VERSION 5.7 ;
  NOWIREEXTENSIONATPIN ON ;
  DIVIDERCHAR "/" ;
  BUSBITCHARS "[]" ;
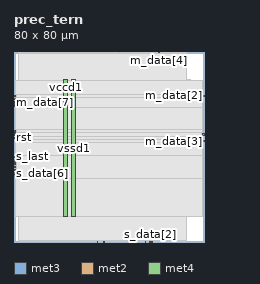
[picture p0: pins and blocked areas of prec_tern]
MACRO prec_tern
  CLASS BLOCK ;
  FOREIGN prec_tern ;
  ORIGIN 0.000 0.000 ;
  SIZE 80.000 BY 80.000 ;
  PIN clk
    DIRECTION INPUT ;
    USE SIGNAL ;
    ANTENNAGATEAREA 1.286700 ;
    ANTENNADIFFAREA 0.434700 ;
    PORT
      LAYER met3 ;
        RECT 0.000 57.160 0.600 57.760 ;
    END
  END clk
  PIN m_data[0]
    DIRECTION OUTPUT ;
    USE SIGNAL ;
    ANTENNADIFFAREA 0.795200 ;
    PORT
      LAYER met2 ;
        RECT 37.810 0.000 38.090 0.280 ;
    END
  END m_data[0]
  PIN m_data[1]
    DIRECTION OUTPUT ;
    USE SIGNAL ;
    ANTENNADIFFAREA 0.795200 ;
    PORT
      LAYER met2 ;
        RECT 35.050 0.000 35.330 0.280 ;
    END
  END m_data[1]
  PIN m_data[2]
    DIRECTION OUTPUT ;
    USE SIGNAL ;
    ANTENNADIFFAREA 0.795200 ;
    PORT
      LAYER met3 ;
        RECT 79.400 61.240 80.000 61.840 ;
    END
  END m_data[2]
  PIN m_data[3]
    DIRECTION OUTPUT ;
    USE SIGNAL ;
    ANTENNADIFFAREA 0.795200 ;
    PORT
      LAYER met3 ;
        RECT 79.400 42.200 80.000 42.800 ;
    END
  END m_data[3]
  PIN m_data[4]
    DIRECTION OUTPUT ;
    USE SIGNAL ;
    ANTENNADIFFAREA 0.795200 ;
    PORT
      LAYER met2 ;
        RECT 60.810 79.720 61.090 80.000 ;
    END
  END m_data[4]
  PIN m_data[5]
    DIRECTION OUTPUT ;
    USE SIGNAL ;
    ANTENNADIFFAREA 0.795200 ;
    PORT
      LAYER met2 ;
        RECT 44.250 79.720 44.530 80.000 ;
    END
  END m_data[5]
  PIN m_data[6]
    DIRECTION OUTPUT ;
    USE SIGNAL ;
    ANTENNADIFFAREA 0.795200 ;
    PORT
      LAYER met3 ;
        RECT 0.000 61.240 0.600 61.840 ;
    END
  END m_data[6]
  PIN m_data[7]
    DIRECTION OUTPUT ;
    USE SIGNAL ;
    ANTENNADIFFAREA 0.795200 ;
    PORT
      LAYER met3 ;
        RECT 0.000 58.520 0.600 59.120 ;
    END
  END m_data[7]
  PIN m_last
    DIRECTION OUTPUT ;
    USE SIGNAL ;
    ANTENNADIFFAREA 0.795200 ;
    PORT
      LAYER met3 ;
        RECT 0.000 59.880 0.600 60.480 ;
    END
  END m_last
  PIN m_ready
    DIRECTION INPUT ;
    USE SIGNAL ;
    ANTENNAGATEAREA 0.647700 ;
    ANTENNADIFFAREA 0.434700 ;
    PORT
      LAYER met3 ;
        RECT 0.000 44.920 0.600 45.520 ;
    END
  END m_ready
  PIN m_valid
    DIRECTION OUTPUT ;
    USE SIGNAL ;
    ANTENNADIFFAREA 0.795200 ;
    PORT
      LAYER met3 ;
        RECT 0.000 46.280 0.600 46.880 ;
    END
  END m_valid
  PIN rst
    DIRECTION INPUT ;
    USE SIGNAL ;
    ANTENNAGATEAREA 0.631200 ;
    ANTENNADIFFAREA 0.434700 ;
    PORT
      LAYER met3 ;
        RECT 0.000 43.560 0.600 44.160 ;
    END
  END rst
  PIN s_data[0]
    DIRECTION INPUT ;
    USE SIGNAL ;
    ANTENNAGATEAREA 0.647700 ;
    ANTENNADIFFAREA 0.434700 ;
    PORT
      LAYER met2 ;
        RECT 55.290 0.000 55.570 0.280 ;
    END
  END s_data[0]
  PIN s_data[1]
    DIRECTION INPUT ;
    USE SIGNAL ;
    ANTENNAGATEAREA 0.647700 ;
    ANTENNADIFFAREA 0.434700 ;
    PORT
      LAYER met2 ;
        RECT 58.050 0.000 58.330 0.280 ;
    END
  END s_data[1]
  PIN s_data[2]
    DIRECTION INPUT ;
    USE SIGNAL ;
    ANTENNAGATEAREA 0.647700 ;
    ANTENNADIFFAREA 0.434700 ;
    PORT
      LAYER met2 ;
        RECT 57.130 0.000 57.410 0.280 ;
    END
  END s_data[2]
  PIN s_data[3]
    DIRECTION INPUT ;
    USE SIGNAL ;
    ANTENNAGATEAREA 0.647700 ;
    ANTENNADIFFAREA 0.434700 ;
    PORT
      LAYER met3 ;
        RECT 79.400 44.920 80.000 45.520 ;
    END
  END s_data[3]
  PIN s_data[4]
    DIRECTION INPUT ;
    USE SIGNAL ;
    ANTENNAGATEAREA 0.647700 ;
    ANTENNADIFFAREA 0.434700 ;
    PORT
      LAYER met3 ;
        RECT 0.000 31.320 0.600 31.920 ;
    END
  END s_data[4]
  PIN s_data[5]
    DIRECTION INPUT ;
    USE SIGNAL ;
    ANTENNAGATEAREA 0.647700 ;
    ANTENNADIFFAREA 0.434700 ;
    PORT
      LAYER met3 ;
        RECT 0.000 27.240 0.600 27.840 ;
    END
  END s_data[5]
  PIN s_data[6]
    DIRECTION INPUT ;
    USE SIGNAL ;
    ANTENNAGATEAREA 0.647700 ;
    ANTENNADIFFAREA 0.434700 ;
    PORT
      LAYER met3 ;
        RECT 0.000 28.600 0.600 29.200 ;
    END
  END s_data[6]
  PIN s_data[7]
    DIRECTION INPUT ;
    USE SIGNAL ;
    ANTENNAGATEAREA 0.647700 ;
    ANTENNADIFFAREA 0.434700 ;
    PORT
      LAYER met3 ;
        RECT 0.000 29.960 0.600 30.560 ;
    END
  END s_data[7]
  PIN s_last
    DIRECTION INPUT ;
    USE SIGNAL ;
    ANTENNAGATEAREA 0.647700 ;
    ANTENNADIFFAREA 0.434700 ;
    PORT
      LAYER met3 ;
        RECT 0.000 32.680 0.600 33.280 ;
    END
  END s_last
  PIN s_ready
    DIRECTION OUTPUT ;
    USE SIGNAL ;
    ANTENNADIFFAREA 0.795200 ;
    PORT
      LAYER met3 ;
        RECT 0.000 35.400 0.600 36.000 ;
    END
  END s_ready
  PIN s_valid
    DIRECTION INPUT ;
    USE SIGNAL ;
    ANTENNAGATEAREA 0.647700 ;
    ANTENNADIFFAREA 0.434700 ;
    PORT
      LAYER met3 ;
        RECT 0.000 34.040 0.600 34.640 ;
    END
  END s_valid
  PIN vccd1
    DIRECTION INOUT ;
    USE POWER ;
    PORT
      LAYER met4 ;
        RECT 21.040 10.640 22.640 68.240 ;
    END
  END vccd1
  PIN vssd1
    DIRECTION INOUT ;
    USE GROUND ;
    PORT
      LAYER met4 ;
        RECT 24.340 10.640 25.940 68.240 ;
    END
  END vssd1
  OBS
      LAYER nwell ;
        RECT 5.330 10.795 74.250 68.190 ;
      LAYER li1 ;
        RECT 5.520 10.795 74.060 68.085 ;
      LAYER met1 ;
        RECT 1.910 10.640 74.360 68.240 ;
      LAYER met2 ;
        RECT 1.930 79.440 43.970 79.720 ;
        RECT 44.810 79.440 60.530 79.720 ;
        RECT 61.370 79.440 72.590 79.720 ;
        RECT 1.930 0.560 72.590 79.440 ;
        RECT 1.930 0.280 34.770 0.560 ;
        RECT 35.610 0.280 37.530 0.560 ;
        RECT 38.370 0.280 55.010 0.560 ;
        RECT 55.850 0.280 56.850 0.560 ;
        RECT 57.690 0.280 57.770 0.560 ;
        RECT 58.610 0.280 72.590 0.560 ;
      LAYER met3 ;
        RECT 0.600 62.240 79.400 68.165 ;
        RECT 1.000 60.840 79.000 62.240 ;
        RECT 1.000 56.760 79.400 60.840 ;
        RECT 0.600 47.280 79.400 56.760 ;
        RECT 1.000 45.920 79.400 47.280 ;
        RECT 1.000 44.520 79.000 45.920 ;
        RECT 1.000 43.200 79.400 44.520 ;
        RECT 1.000 43.160 79.000 43.200 ;
        RECT 0.600 41.800 79.000 43.160 ;
        RECT 0.600 36.400 79.400 41.800 ;
        RECT 1.000 26.840 79.400 36.400 ;
        RECT 0.600 10.715 79.400 26.840 ;
  END
END prec_tern
END LIBRARY

